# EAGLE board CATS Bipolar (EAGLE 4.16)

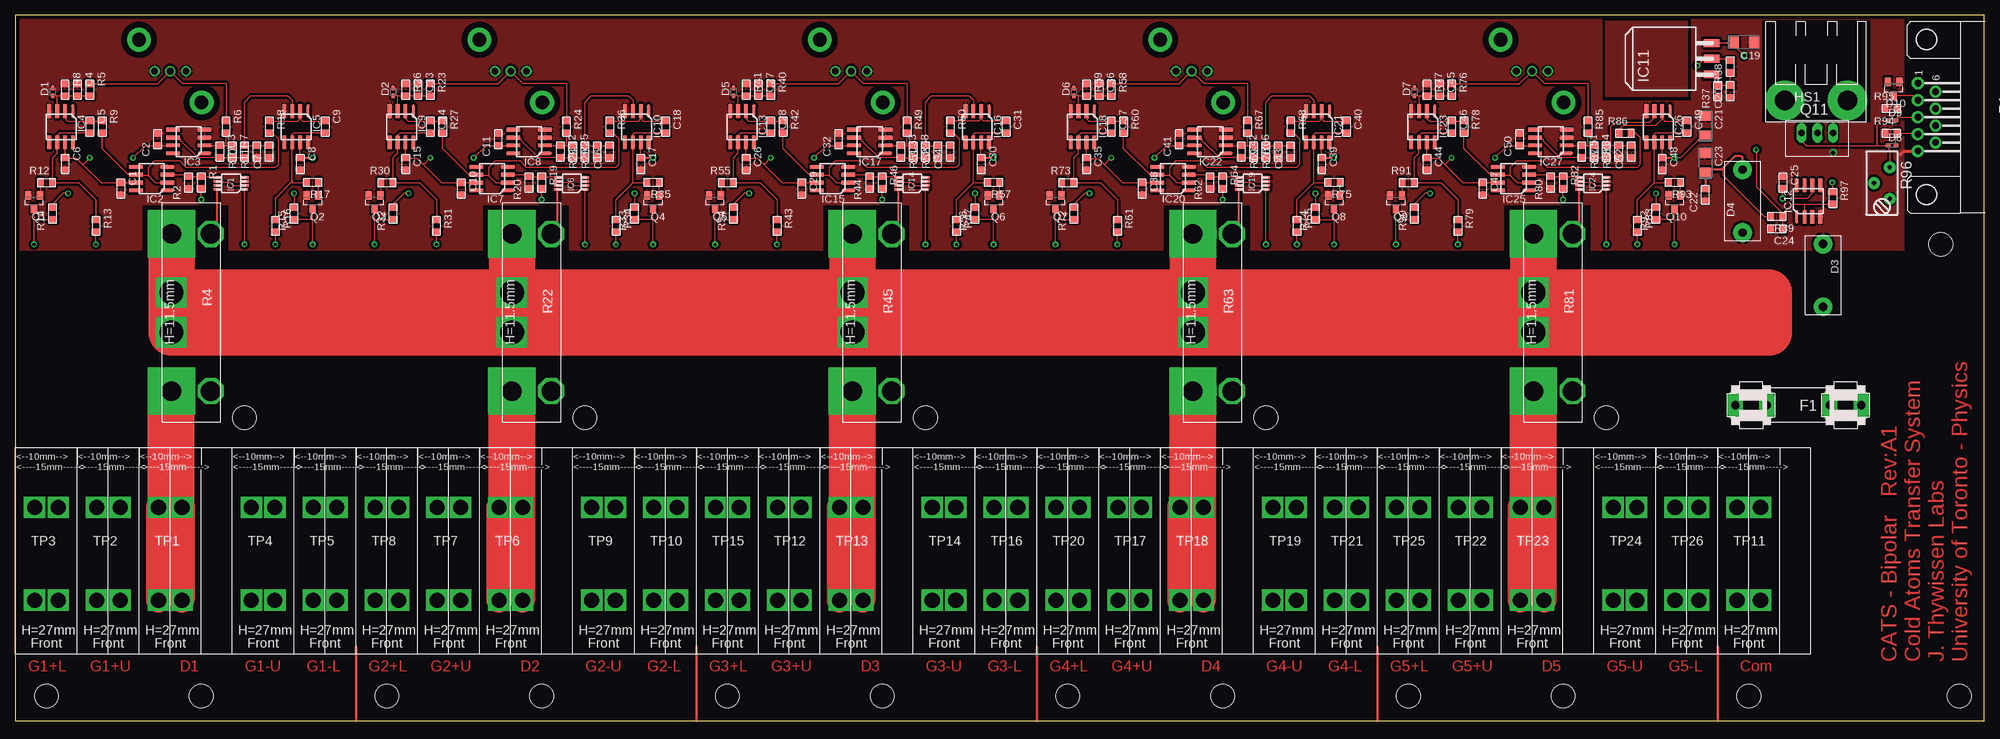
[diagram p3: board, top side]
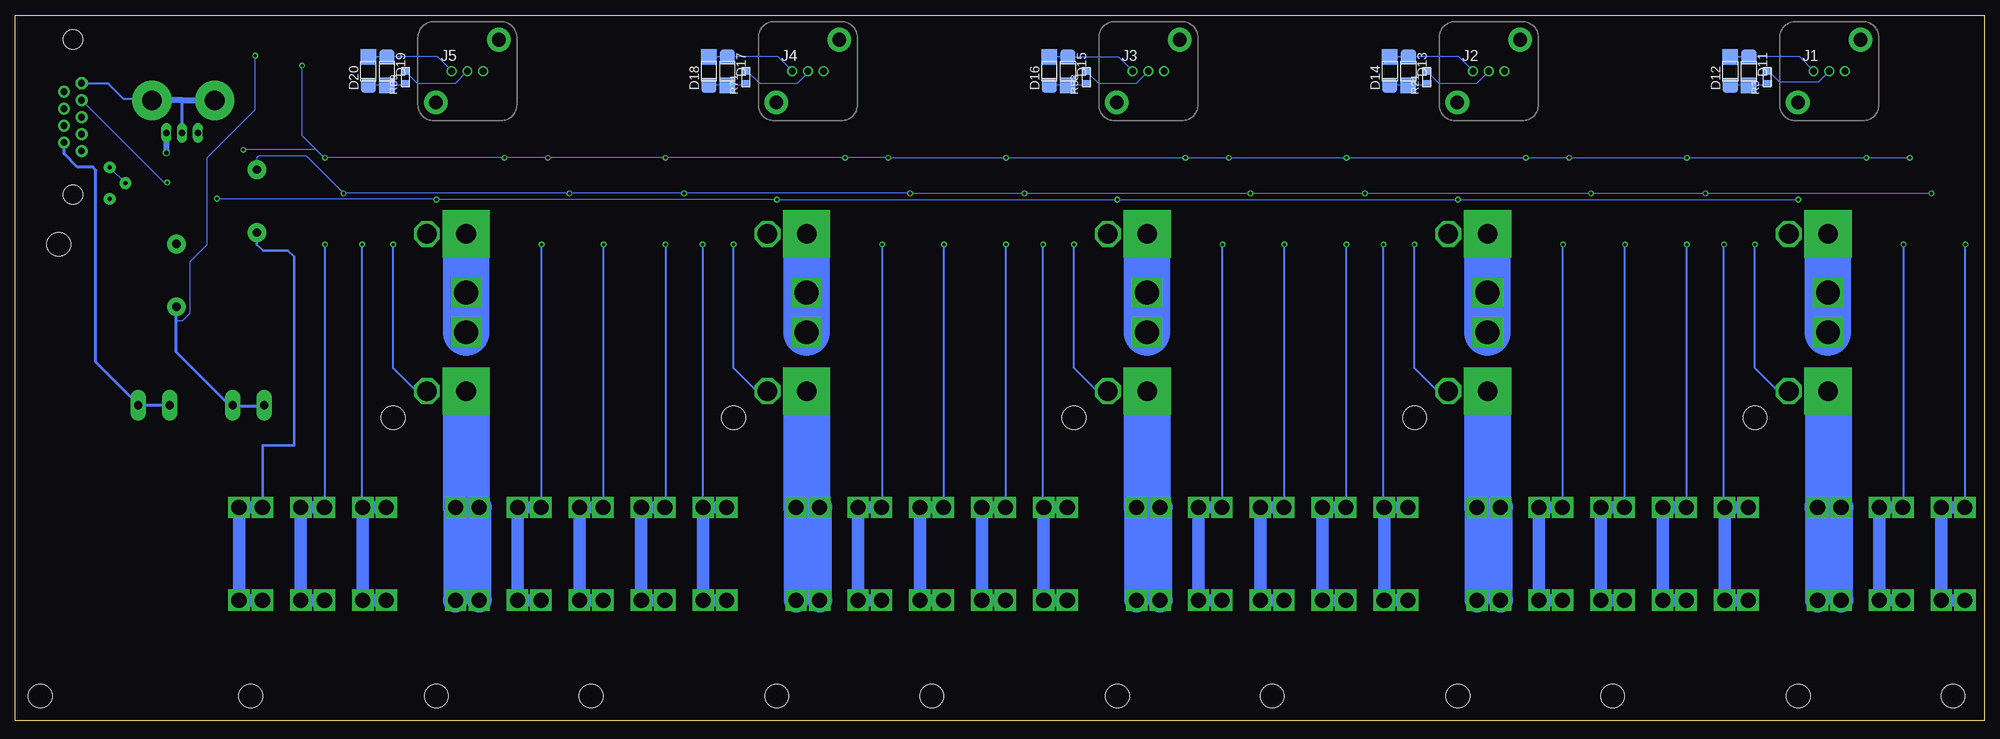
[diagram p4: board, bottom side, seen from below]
Size 318 x 114 mm. Coordinates in mm from the lower left corner, seen from the top.
Outline: 0,0 318,0 318,114 0,114 0,0
Copper layers (1*16): Top 0.035mm / dielectric 1.5mm / Bottom 0.035mm
Design rules "DRC standard check (7mil trace and gap, 20mil drill, etc)": minimum track width 7mil, minimum drill 20mil, track to track 7mil, track to pad 7mil, pad to pad 7mil, via to via 7mil, smd to smd 7mil, copper to edge 25mil, drill to drill 8mil, minimum pad ring 10mil, minimum via ring 8mil, stop-mask expansion 4mil, vias tented up to drill 0mil, thermal gap 10mil
Net classes: 0 default: clearance 0.406 mm; 1 Power: width 1.016 mm, drill 0.178 mm, clearance 3.175 mm
Holes 3.86 mm at 5,4 30,4 60,4 85,4 115,4 140,4 170,4 195,4 225,4 250,4 280,4 314,4 311,77 37,49 92,49 147,49 202,49 257,49
bKeepout: area 1.5,0.5 to 8.5,7.5; area 26.5,0.5 to 33.5,7.5; area 56.5,0.5 to 63.5,7.5; area 81.5,0.5 to 88.5,7.5; area 111.5,0.5 to 118.5,7.5; area 136.5,0.5 to 143.5,7.5; area 166.5,0.5 to 173.5,7.5; area 191.5,0.5 to 198.5,7.5; area 221.5,0.5 to 228.5,7.5; area 246.5,0.5 to 253.5,7.5; area 276.5,0.5 to 283.5,7.5; area 310.5,0.5 to 317.5,7.5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
tRestrict: 23 lines

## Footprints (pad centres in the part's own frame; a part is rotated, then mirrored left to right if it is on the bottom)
2012(0805) = smd 1.016 x 1.397: 1 -0.953,0; 2 0.953,0
EIA-A = smd 1.6 x 1.8: 1 -1.27,0; 2 1.905,0
SOD523 = smd 0.7 x 0.5: A 1.27,0; C 0,0
PASSIVE_0.4" = drill 1.321 pad 3.048 round: 1 -5.08,0; 2 5.08,0
SOT23 = smd 1 x 1.4: 1 -0.953,-0.953; 2 0.953,-0.953; 3 0,1.27
1209 = smd 2.5 x 2.5: A 2.3,0; K -2.3,0
FUSE = drill 1.321 pad 2.54 long: 1A -10.16,0; 1B -5.08,0; 2A 10.16,0; 2B 5.08,0
HEATSINK-5(TO-220) = drill 3.175 pad 6.35 round: 1 -5.08,0; 2 5.08,0
MSOP8 = smd 0.4 x 1.2: 1 -0.635,-1.905; 2 0,-1.905; 3 0.635,-1.905; 4 1.27,-1.905; 5 1.27,2.54; 6 0.635,2.54; 7 0,2.54; 8 -0.635,2.54
SOIC-8 = smd 0.6 x 2.2: 1 -1.27,-2.54; 2 0,-2.54; 3 1.27,-2.54; 4 2.54,-2.54; 5 2.54,2.54; 6 1.27,2.54; 7 0,2.54; 8 -1.27,2.54
TO263 = smd 1.27 x 2.54: 1 -2.54,0; 2 0,0; 3 2.54,0
CONN-BNC-AMP-TYPE1VERT = drill 1.067 round: CONDUCTOR 0,0; SHIELD1 -2.54,0; SHIELD2 2.54,0 | drill 2.184 pad 3.81 round: MTG1 -5.08,-5.08; MTG2 5.08,5.08
CONN-DB9-HORIZ1 = drill 1.067 pad 1.905 octagon: 1 -5.486,-1.422 | drill 1.067 pad 1.905 round: 2 -2.743,-1.422; 3 0,-1.422; 4 2.743,-1.422; 5 5.486,-1.422; 6 -4.115,1.422; 7 -1.372,1.422; 8 1.372,1.422; 9 4.115,1.422 | hole 3.175: -12.522,0; 12.522,0
TO220-VERTICAL = drill 1.067 long: 1 -2.54,0; 2 0,0; 3 2.54,0
OHMITE_650 = drill 3.175 pad 7.62 square: CURRENT1 -12.7,-3.81; CURRENT2 12.7,-3.81 | drill 3.175 octagon: SENSE1 -12.7,2.54; SENSE2 12.7,2.54
BOURNS-3296Y = drill 0.711 pad 1.905 round: CCW 2.54,1.27; CW -2.54,1.27; W 0,-1.27
PHEONIX_ZFKDS-10/15MM-TERMINAL-BLOCK = drill 2.438 square: T@1 -1.9,-7.5; T@2 1.9,-7.5; T@3 1.9,7.5; T@4 -1.9,7.5

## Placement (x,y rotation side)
C1  0.1uF  [2012(0805)]  17,86 270 top
C2  0.1uF  [2012(0805)]  23,94 90 top
C3  1nF  [2012(0805)]  33,92 270 top
C4  10nF  [2012(0805)]  10,102 270 top
C5  100pF  [2012(0805)]  12,96 270 top
C6  0.1uF  [2012(0805)]  8,90 270 top
C7  10nF  [2012(0805)]  41,92 90 top
C8  0.1uF  [2012(0805)]  46,90 270 top
C9  100pF  [2012(0805)]  50,96 270 top
C10  0.1uF  [2012(0805)]  72,86 270 top
C11  0.1uF  [2012(0805)]  78,94 90 top
C12  1nF  [2012(0805)]  88,92 270 top
C13  10nF  [2012(0805)]  65,102 270 top
C14  100pF  [2012(0805)]  67,96 270 top
C15  0.1uF  [2012(0805)]  63,90 270 top
C16  10nF  [2012(0805)]  96,92 90 top
C17  0.1uF  [2012(0805)]  101,90 270 top
C18  100pF  [2012(0805)]  105,96 270 top
C19  100uF/35V  [EIA-A]  279.5,109.65 180 top
C20  0.1uF  [2012(0805)]  277,101.75 90 top
C21  100uF/35V  [EIA-A]  273,96.5 270 top
C22  0.1uF  [2012(0805)]  273,85 90 top
C23  100uF/35V  [EIA-A]  273,90.5 270 top
C24  0.1uF  [2012(0805)]  284.5,79.5 180 top
C25  0.1uF  [2012(0805)]  285.5,87 270 top
C26  0.1uF  [2012(0805)]  118,90 270 top
C27  10nF  [2012(0805)]  120,102 270 top
C28  100pF  [2012(0805)]  122,96 270 top
C29  0.1uF  [2012(0805)]  127,86 270 top
C30  0.1uF  [2012(0805)]  156,90 270 top
C31  100pF  [2012(0805)]  160,96 270 top
C32  0.1uF  [2012(0805)]  133,94 90 top
C33  1nF  [2012(0805)]  143,92 270 top
C34  10nF  [2012(0805)]  151,92 90 top
C35  0.1uF  [2012(0805)]  173,90 270 top
C36  10nF  [2012(0805)]  175,102 270 top
C37  100pF  [2012(0805)]  177,96 270 top
C38  0.1uF  [2012(0805)]  182,86 270 top
C39  0.1uF  [2012(0805)]  211,90 270 top
C40  100pF  [2012(0805)]  215,96 270 top
C41  0.1uF  [2012(0805)]  188,94 90 top
C42  1nF  [2012(0805)]  198,92 270 top
C43  10nF  [2012(0805)]  206,92 90 top
C44  0.1uF  [2012(0805)]  228,90 270 top
C45  10nF  [2012(0805)]  230,102 270 top
C46  100pF  [2012(0805)]  232,96 270 top
C47  0.1uF  [2012(0805)]  237,86 270 top
C48  0.1uF  [2012(0805)]  266,90 270 top
C49  100pF  [2012(0805)]  270,96 270 top
C50  0.1uF  [2012(0805)]  243,94 90 top
C51  1nF  [2012(0805)]  253,92 270 top
C52  10nF  [2012(0805)]  261,92 90 top
D1  1N4148WT  [SOD523]  6,101 90 top
D2  1N4148WT  [SOD523]  61,101 90 top
D3  1N4750A  [PASSIVE_0.4"]  292,72 270 top
D4  1N4740A  [PASSIVE_0.4"]  279,84 90 top
D5  1N4148WT  [SOD523]  116,101 90 top
D6  1N4148WT  [SOD523]  171,101 90 top
D7  1N4148WT  [SOD523]  226,101 90 top
D8  1N4148WT  [SOD523]  302.5,93 0 top
D9  1N4148WT  [SOD523]  302.5,97 0 top
D10  BZX84-C5V1  [SOT23]  303.4,102.3 180 top
D11  SML-LXL1209UPGC  [1209]  38,105 270 bottom
D12  SML-LXL1209SOC  [1209]  41,105 90 bottom
D13  SML-LXL1209UPGC  [1209]  93,105 270 bottom
D14  SML-LXL1209SOC  [1209]  96,105 90 bottom
D15  SML-LXL1209UPGC  [1209]  148,105 270 bottom
D16  SML-LXL1209SOC  [1209]  151,105 90 bottom
D17  SML-LXL1209UPGC  [1209]  203,105 270 bottom
D18  SML-LXL1209SOC  [1209]  206,105 90 bottom
D19  SML-LXL1209UPGC  [1209]  258,105 270 bottom
D20  SML-LXL1209SOC  [1209]  261,105 90 bottom
F1  0.1A-5x20  [FUSE]  288,51 180 top
HS1  634-20ABP  [HEATSINK-5(TO-220)]  290.89,100.28 0 top
IC1  AD8212RMZ  [MSOP8]  35.15,86.54 90 top
IC2  AD820ARZ  [SOIC-8]  22,87 90 top
IC3  AD820ARZ  [SOIC-8]  28,93 90 top
IC4  AD820ARZ  [SOIC-8]  8,96 180 top
IC5  AD820ARZ  [SOIC-8]  46,96 180 top
IC6  AD8212RMZ  [MSOP8]  90.15,86.54 90 top
IC7  AD820ARZ  [SOIC-8]  77,87 90 top
IC8  AD820ARZ  [SOIC-8]  83,93 90 top
IC9  AD820ARZ  [SOIC-8]  63,96 180 top
IC10  AD820ARZ  [SOIC-8]  101,96 180 top
IC11  LM1086CS-ADJ  [TO263]  274,107 90 top
IC12  ADR435AR(Z)  [SOIC-8]  289,84 0 top
IC13  AD820ARZ  [SOIC-8]  118,96 180 top
IC14  AD8212RMZ  [MSOP8]  145.15,86.54 90 top
IC15  AD820ARZ  [SOIC-8]  132,87 90 top
IC16  AD820ARZ  [SOIC-8]  156,96 180 top
IC17  AD820ARZ  [SOIC-8]  138,93 90 top
IC18  AD820ARZ  [SOIC-8]  173,96 180 top
IC19  AD8212RMZ  [MSOP8]  200.15,86.54 90 top
IC20  AD820ARZ  [SOIC-8]  187,87 90 top
IC21  AD820ARZ  [SOIC-8]  211,96 180 top
IC22  AD820ARZ  [SOIC-8]  193,93 90 top
IC23  AD820ARZ  [SOIC-8]  228,96 180 top
IC24  AD8212RMZ  [MSOP8]  255.15,86.54 90 top
IC25  AD820ARZ  [SOIC-8]  242,87 90 top
IC26  AD820ARZ  [SOIC-8]  266,96 180 top
IC27  AD820ARZ  [SOIC-8]  248,93 90 top
J1  Amp 227673-1  [CONN-BNC-AMP-TYPE1VERT]  25,105 0 bottom
J2  Amp 227673-1  [CONN-BNC-AMP-TYPE1VERT]  80,105 0 bottom
J3  Amp 227673-1  [CONN-BNC-AMP-TYPE1VERT]  135,105 0 bottom
J4  Amp 227673-1  [CONN-BNC-AMP-TYPE1VERT]  190,105 0 bottom
J5  Amp 227673-1  [CONN-BNC-AMP-TYPE1VERT]  245,105 0 bottom
P1  [CONN-DB9-HORIZ1]  308.74,97.57 270 top
Q1  MMBT5551  [SOT23]  3,84 180 top
Q2  MMBT5551  [SOT23]  48,84 180 top
Q3  MMBT5551  [SOT23]  58,84 180 top
Q4  MMBT5551  [SOT23]  103,84 180 top
Q5  MMBT5551  [SOT23]  113,84 180 top
Q6  MMBT5551  [SOT23]  158,84 180 top
Q7  MMBT5551  [SOT23]  168,84 180 top
Q8  MMBT5551  [SOT23]  213,84 180 top
Q9  MMBT5551  [SOT23]  223,84 180 top
Q10  MMBT5551  [SOT23]  268,84 180 top
Q11  NDP6060L  [TO220-VERTICAL]  291.08,95.04 0 top
R1  75K  [2012(0805)]  30,87 270 top
R2  3.92K  [2012(0805)]  28,87 90 top
R3  3.01K  [2012(0805)]  35,104 90 bottom
R4  2mOhm/5W  [OHMITE_650]  29,66 270 top
R5  9.09K  [2012(0805)]  12,102 270 top
R6  10K  [2012(0805)]  34,96 270 top
R7  10K  [2012(0805)]  35,92 270 top
R8  1K  [2012(0805)]  8,102 270 top
R9  3.92K  [2012(0805)]  14,96 270 top
R10  9.09K  [2012(0805)]  37,92 90 top
R11  1K  [2012(0805)]  39,92 90 top
R12  10K  [2012(0805)]  5,87 0 top
R13  100  [2012(0805)]  13,80 270 top
R14  2K  [2012(0805)]  6,82 90 top
R15  2K  [2012(0805)]  45,82 90 top
R16  100  [2012(0805)]  42,80 270 top
R17  10K  [2012(0805)]  48,87 180 top
R18  3.92K  [2012(0805)]  41,96 270 top
R19  75K  [2012(0805)]  85,87 270 top
R20  3.92K  [2012(0805)]  83,87 90 top
R21  3.01K  [2012(0805)]  90,104 90 bottom
R22  2mOhm/5W  [OHMITE_650]  84,66 270 top
R23  9.09K  [2012(0805)]  67,102 270 top
R24  10K  [2012(0805)]  89,96 270 top
R25  10K  [2012(0805)]  90,92 270 top
R26  1K  [2012(0805)]  63,102 270 top
R27  3.92K  [2012(0805)]  69,96 270 top
R28  9.09K  [2012(0805)]  92,92 90 top
R29  1K  [2012(0805)]  94,92 90 top
R30  10K  [2012(0805)]  60,87 0 top
R31  100  [2012(0805)]  68,80 270 top
R32  2K  [2012(0805)]  61,82 90 top
R33  2K  [2012(0805)]  100,82 90 top
R34  100  [2012(0805)]  97,80 270 top
R35  10K  [2012(0805)]  103,87 180 top
R36  3.92K  [2012(0805)]  96,96 270 top
R37  1.47K  [2012(0805)]  275,101.75 90 top
R38  124  [2012(0805)]  277,105.75 90 top
R39  301  [2012(0805)]  284.5,81.5 180 top
R40  9.09K  [2012(0805)]  122,102 270 top
R41  1K  [2012(0805)]  118,102 270 top
R42  3.92K  [2012(0805)]  124,96 270 top
R43  100  [2012(0805)]  123,80 270 top
R44  3.92K  [2012(0805)]  138,87 90 top
R45  2mOhm/5W  [OHMITE_650]  139,66 270 top
R46  75K  [2012(0805)]  140,87 270 top
R47  100  [2012(0805)]  152,80 270 top
R48  10K  [2012(0805)]  145,92 270 top
R49  10K  [2012(0805)]  144,96 270 top
R50  3.92K  [2012(0805)]  151,96 270 top
R51  9.09K  [2012(0805)]  147,92 90 top
R52  1K  [2012(0805)]  149,92 90 top
R53  3.01K  [2012(0805)]  145,104 90 bottom
R54  2K  [2012(0805)]  116,82 90 top
R55  10K  [2012(0805)]  115,87 0 top
R56  2K  [2012(0805)]  155,82 90 top
R57  10K  [2012(0805)]  158,87 180 top
R58  9.09K  [2012(0805)]  177,102 270 top
R59  1K  [2012(0805)]  173,102 270 top
R60  3.92K  [2012(0805)]  179,96 270 top
R61  100  [2012(0805)]  178,80 270 top
R62  3.92K  [2012(0805)]  193,87 90 top
R63  2mOhm/5W  [OHMITE_650]  194,66 270 top
R64  75K  [2012(0805)]  195,87 270 top
R65  100  [2012(0805)]  207,80 270 top
R66  10K  [2012(0805)]  200,92 270 top
R67  10K  [2012(0805)]  199,96 270 top
R68  3.92K  [2012(0805)]  206,96 270 top
R69  9.09K  [2012(0805)]  202,92 90 top
R70  1K  [2012(0805)]  204,92 90 top
R71  3.01K  [2012(0805)]  200,104 90 bottom
R72  2K  [2012(0805)]  171,82 90 top
R73  10K  [2012(0805)]  170,87 0 top
R74  2K  [2012(0805)]  210,82 90 top
R75  10K  [2012(0805)]  213,87 180 top
R76  9.09K  [2012(0805)]  232,102 270 top
R77  1K  [2012(0805)]  228,102 270 top
R78  3.92K  [2012(0805)]  234,96 270 top
R79  100  [2012(0805)]  233,80 270 top
R80  3.92K  [2012(0805)]  248,87 90 top
R81  2mOhm/5W  [OHMITE_650]  249,66 270 top
R82  75K  [2012(0805)]  250,87 270 top
R83  100  [2012(0805)]  262,80 270 top
R84  10K  [2012(0805)]  255,92 270 top
R85  10K  [2012(0805)]  254,96 270 top
R86  3.92K  [2012(0805)]  260,95 0 top
R87  9.09K  [2012(0805)]  257,92 90 top
R88  1K  [2012(0805)]  259,92 90 top
R89  3.01K  [2012(0805)]  255,104 90 bottom
R90  2K  [2012(0805)]  226,82 90 top
R91  10K  [2012(0805)]  225,87 0 top
R92  2K  [2012(0805)]  265,82 90 top
R93  10K  [2012(0805)]  268,87 180 top
R94  ???  [2012(0805)]  303,95 0 top
R95  ???  [2012(0805)]  303,99 0 top
R96  3296Y-10K  [BOURNS-3296Y]  301.5,86.9 270 top
R97  1K  [2012(0805)]  293.55,84.5 270 top
TP1  Pheonix-1987631  [PHEONIX_ZFKDS-10/15MM-TERMINAL-BLOCK]  25,27 0 top
TP2  Pheonix-1987628  [PHEONIX_ZFKDS-10/15MM-TERMINAL-BLOCK]  15,27 0 top
TP3  Pheonix-1987628  [PHEONIX_ZFKDS-10/15MM-TERMINAL-BLOCK]  5,27 0 top
TP4  Pheonix-1987628  [PHEONIX_ZFKDS-10/15MM-TERMINAL-BLOCK]  40,27 0 top
TP5  Pheonix-1987628  [PHEONIX_ZFKDS-10/15MM-TERMINAL-BLOCK]  50,27 0 top
TP6  Pheonix-1987631  [PHEONIX_ZFKDS-10/15MM-TERMINAL-BLOCK]  80,27 0 top
TP7  Pheonix-1987628  [PHEONIX_ZFKDS-10/15MM-TERMINAL-BLOCK]  70,27 0 top
TP8  Pheonix-1987628  [PHEONIX_ZFKDS-10/15MM-TERMINAL-BLOCK]  60,27 0 top
TP9  Pheonix-1987628  [PHEONIX_ZFKDS-10/15MM-TERMINAL-BLOCK]  95,27 0 top
TP10  Pheonix-1987628  [PHEONIX_ZFKDS-10/15MM-TERMINAL-BLOCK]  105,27 0 top
TP11  Pheonix-1987628  [PHEONIX_ZFKDS-10/15MM-TERMINAL-BLOCK]  280,27 0 top
TP12  Pheonix-1987628  [PHEONIX_ZFKDS-10/15MM-TERMINAL-BLOCK]  125,27 0 top
TP13  Pheonix-1987631  [PHEONIX_ZFKDS-10/15MM-TERMINAL-BLOCK]  135,27 0 top
TP14  Pheonix-1987628  [PHEONIX_ZFKDS-10/15MM-TERMINAL-BLOCK]  150,27 0 top
TP15  Pheonix-1987628  [PHEONIX_ZFKDS-10/15MM-TERMINAL-BLOCK]  115,27 0 top
TP16  Pheonix-1987628  [PHEONIX_ZFKDS-10/15MM-TERMINAL-BLOCK]  160,27 0 top
TP17  Pheonix-1987628  [PHEONIX_ZFKDS-10/15MM-TERMINAL-BLOCK]  180,27 0 top
TP18  Pheonix-1987631  [PHEONIX_ZFKDS-10/15MM-TERMINAL-BLOCK]  190,27 0 top
TP19  Pheonix-1987628  [PHEONIX_ZFKDS-10/15MM-TERMINAL-BLOCK]  205,27 0 top
TP20  Pheonix-1987628  [PHEONIX_ZFKDS-10/15MM-TERMINAL-BLOCK]  170,27 0 top
TP21  Pheonix-1987628  [PHEONIX_ZFKDS-10/15MM-TERMINAL-BLOCK]  215,27 0 top
TP22  Pheonix-1987628  [PHEONIX_ZFKDS-10/15MM-TERMINAL-BLOCK]  235,27 0 top
TP23  Pheonix-1987631  [PHEONIX_ZFKDS-10/15MM-TERMINAL-BLOCK]  245,27 0 top
TP24  Pheonix-1987628  [PHEONIX_ZFKDS-10/15MM-TERMINAL-BLOCK]  260,27 0 top
TP25  Pheonix-1987628  [PHEONIX_ZFKDS-10/15MM-TERMINAL-BLOCK]  225,27 0 top
TP26  Pheonix-1987628  [PHEONIX_ZFKDS-10/15MM-TERMINAL-BLOCK]  270,27 0 top
U$106  [TITLEBLOCK_PCB]  not placed on the board

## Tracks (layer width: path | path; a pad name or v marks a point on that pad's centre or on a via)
+5.0V  (via drill 0.51)
  Top 0.18: v30,84.25 R1.2 | v85,84.25 R19.2 | v140,84.25 R46.2 | R64.2 v195,84.25 | v250,84.25 R82.2 | IC12.6 290.27,85.27 289.5,84.5 285.5,84.5 | 285.5,84.5 285.45,84.5 v285.45,84.4 | 285.5,84.5 C25.2
  Bottom 0.18: v30,84.25 v85,84.25 v140,84.25 v195,84.25 v250,84.25 | v250,84.25 250,84.2 | v250,84.25 250,84.3 285.35,84.3 285.35,84.35 285.5,84.5 285.45,84.5 v285.45,84.4
+10V  (via drill 0.51)
  Top 0.18: R14.2 6,83.5 7.75,85.25 v8.5,85.25 | R32.2 61,83.5 62.75,85.25 v63.5,85.25 | v45,85.25 R15.2 | v100,85.25 R33.2 | R54.2 116,83.5 117.75,85.25 v118.5,85.25 | v155,85.25 R56.2 | R72.2 171,83.5 172.75,85.25 v173.5,85.25 | v210,85.25 R74.2 | R90.2 226,83.5 227.75,85.25 v228.5,85.25 | v265,85.25 R92.2 | C23.2 273,88.5 273.58,89.08 | R39.2 282.5,81.5 275.8,88.2 275.8,89.08
  Top 0.36: 273.58,89.08 275.8,89.08 275.75,89.25 277.75,91.25 278.75,91.25 279,91 D4.2 | C23.2 C22.2
  Bottom 0.18: v8.5,85.25 v45,85.25 v63.5,85.25 v100,85.25 v118.5,85.25 v155,85.25 v173.5,85.25 v210,85.25 v228.5,85.25 v265,85.25 271,91.25 278.75,91.25 279,91 279,89 D4.2
+16V  (via drill 0.51)
  Top 0.18: IC4.7 8,91 8.1,90.9 C6.1 7.9,90.9 9.9,90.9 10.9,89.9 | IC2.7 17.1,87 17,86.9 C1.1 13.85,86.95 10.9,89.9 | 23,93 22.9,93 22.9,93.05 C2.1 23,93 | 23,93 IC3.7 | 46,93.5 IC5.7 C8.1 | 10.9,89.9 10.9,90 11,90 v12,91 | v19,91 21,93 23,93 | IC9.7 63,91 63.1,90.9 C15.1 62.9,90.9 64.9,90.9 65.9,89.9 | IC7.7 72.1,87 72,86.9 C10.1 68.85,86.95 65.9,89.9 | 78,93 77.9,93 77.9,93.05 C11.1 78,93 | 78,93 IC8.7 | 101,93.5 IC10.7 C17.1 | 65.9,89.9 65.9,90 66,90 v67,91 | v74,91 76,93 78,93 | IC13.7 118,91 118.1,90.9 C26.1 117.9,90.9 119.9,90.9 120.9,89.9 | IC15.7 127.1,87 127,86.9 C29.1 123.85,86.95 120.9,89.9 | 133,93 132.9,93 132.9,93.05 C32.1 133,93 | 133,93 IC17.7 | 156,93.5 IC16.7 C30.1 | 120.9,89.9 120.9,90 121,90 v122,91 | v129,91 131,93 133,93 | IC18.7 173,91 173.1,90.9 C35.1 172.9,90.9 174.9,90.9 175.9,89.9 | IC20.7 182.1,87 182,86.9 C38.1 178.85,86.95 175.9,89.9 | 188,93 187.9,93 187.9,93.05 C41.1 188,93 | 188,93 IC22.7 | 211,93.5 IC21.7 C39.1 | 175.9,89.9 175.9,90 176,90 v177,91 | v184,91 186,93 188,93 | IC23.7 228,91 228.1,90.9 C44.1 227.9,90.9 229.9,90.9 230.9,89.9 | IC25.7 237.1,87 237,86.9 C47.1 233.85,86.95 230.9,89.9 | 243,93 242.9,93 242.9,93.05 C50.1 243,93 | 243,93 IC27.7 | 266,93.5 IC26.7 C48.1 | 230.9,89.9 230.9,90 231,90 v232,91 | v239,91 241,93 243,93 | v268,91 269,91 272,94 272.4,94 C21.2 | 285.5,81.5 R39.1 | C24.1 285.45,81.45 285.5,81.5 | 285.5,82 285.5,81.5 | 285.5,82 287,83.5 289,83.5 | 289,83.5 IC12.2 | R38.2 277,106.75 276.75,107 IC11.2 272.8,107 v271.7,105.9 | R97.2 293.5,83.55 293.5,83.5 289,83.5 | C21.2 | C21.2 273,94.75 | 285.5,82 281.2,86.3 v281.2,92.3
  Top 0.36: C8.1 47.95,90.95 v48,91 | C17.1 102.95,90.95 v103,91 | C30.1 157.95,90.95 v158,91 | C39.1 212.95,90.95 v213,91 | C48.1 267.95,90.95 v268,91
  Bottom 0.18: v12,91 v19,91 v48,91 v67,91 v74,91 v103,91 v122,91 v129,91 v158,91 v177,91 v184,91 v213,91 v232,91 v239,91 v268,91 268.1,91 269.4,92.3 | v271.7,105.9 271.7,94.6 269.4,92.3 | 269.4,92.3 v281.2,92.3
  pour Top: 257,101 270,101 270,113 257,113
+V-COIL  (via drill 3.86)
  Top 2: R4.CURRENT1 | R22.CURRENT1 | R45.CURRENT1 | R63.CURRENT1 | R81.CURRENT1
  Top 7.5: v25.2,69.2 R4.CURRENT1 | v25.2,69.2 v25.2,62.8 v80.2,62.8 | v80.2,69.2 R22.CURRENT1 | v80.2,69.2 v80.2,62.8 | v80.2,69.2 v25.2,69.2 | v135.2,69.2 R45.CURRENT1 | v135.2,69.2 v135.2,62.8 | v135.2,69.2 v80.2,69.2 | v135.2,62.8 v80.2,62.8 | v190.2,69.2 R63.CURRENT1 | v190.2,69.2 v190.2,62.8 | v190.2,69.2 v135.2,69.2 | v190.2,62.8 v135.2,62.8 | v245.2,69.2 R81.CURRENT1 | v245.2,69.2 v245.2,62.8 | v190.2,69.2 v245.2,69.2 | v190.2,62.8 v245.2,62.8 | v245.2,62.8 283.2,62.8 283.2,69.2 v245.2,69.2
  Bottom 7.5: R4.CURRENT1 v25.2,69.2 v25.2,62.8 | R22.CURRENT1 v80.2,69.2 v80.2,62.8 | R45.CURRENT1 v135.2,69.2 v135.2,62.8 | R63.CURRENT1 v190.2,69.2 v190.2,62.8 | R81.CURRENT1 v245.2,69.2 v245.2,62.8
AGND  (via drill 0.71)
  Top 0.5: P1.5 305.08,92.08 304.5,91.5
  Bottom 0.18: v293.62,91.82 293.6,91.8 | D11.K 40.7,107.3 40.75,107.25 40.75,107.3 D12.A 29.8,107.3 27.5,105 J1.SHIELD1 | D13.K 93,107.25 93.05,107.3 D14.A 84.8,107.3 82.5,105 J2.SHIELD1 | D15.K 150.95,107.3 151,107.25 D16.A 139.8,107.3 137.5,105 J3.SHIELD1 | D17.K 205.95,107.3 206,107.25 D18.A 194.8,107.3 192.5,105 J4.SHIELD1 | D19.K 260.95,107.3 261,107.25 D20.A 249.8,107.3 247.5,105 J5.SHIELD1
  Bottom 0.4: D4.1 279,77 278,76 274,76 273,75 273,74
  Bottom 0.406: TP11.T@4 278.1,44.5 273,44.5 273,74
  Bottom 1: 293.6,91.8 293.6,95
  Bottom 2: TP11.T@1 TP11.T@2 TP11.T@3 TP11.T@4
  pour Top (rank 2): 305,114 305,76 0,76 0,114
N$1
  Top 0.18: IC2.3 27.63,88.27 28,87.9 R2.2 29.95,87.95 30,87.9 R1.1 32.45,87.95 IC1.5
N$2
  Top 0.18: R9.2 14,92.5 18.23,88.27 IC2.6 19.4,88.27 19.3,88.2 21.4,88.2 21.55,88.05 | IC2.2 22.6,87 21.55,88.05 | R18.2 41.45,95.05 42.5,94 42.5,90 42,89.5 27.5,89.5 26.5,90.5 22.5,90.5 21.5,89.5 21.5,88 21.55,88 21.55,88.05
N$3  (via drill 0.51)
  Top 0.18: IC1.1 37.05,86 37,86 v37,77
  Bottom 0.36: R4.SENSE2 33.3,53.3 37,57 v37,77
N$4
  Top 0.36: R4.SENSE1 31.54,78.5 31.5,78.5 32.61,79.61 IC1.8
N$5
  Top 0.18: IC1.2 35.16,86.54 34.6,87.1 32.8,87.1 32.7,87.17 IC1.6
N$6
  Top 0.18: 34,96.9 R6.1 34,103.05 26.95,103.05 J1.CONDUCTOR 22.95,102.95 R5.1
  Bottom 0.18: R3.2 34.7,104.95 33,103.25 26.75,103.25 J1.CONDUCTOR
N$7
  Top 0.18: 46,97.3 IC5.2 | 46,97.3 46.4,96.9 49.9,96.9 50,97 C9.1 | R18.1 45.65,96.95 46,97.3
N$8
  Top 4: TP1.T@1 TP1.T@4 25.2,34.5 | TP1.T@2 TP1.T@3 25.2,34.5 | 25.2,34.5 25.19,34.5
  Top 7.6: 25.19,34.5 R4.CURRENT2
  Bottom 4: TP1.T@1 TP1.T@4 | TP1.T@3 TP1.T@2
  Bottom 7.6: R4.CURRENT2 25.19,34.5
N$9
  Top 0.18: C9.2 50,95 49.9,95.1 45,95.1 44.73,94.83 IC5.6 44.73,87.23 | 44.73,87.23 44.73,87 R17.2 | 44.73,87.23 42,84.5 R16.1
N$10  (via drill 0.51)
  Top 0.18: v42,77 R16.2
  Bottom 0.18: TP4.T@3 42,34.5
  Bottom 0.36: 42,34.5 v42,77
  Bottom 2: TP4.T@1 TP4.T@2 TP4.T@3 TP4.T@4
N$11
  Top 0.18: R10.1 35.05,91.05 35,91 R7.2 33.05,91.05 33,91.1 | 33,91.1 C3.2 | 33,91.1 29.4,91.1 26.7,93.8 26.7,94 26.5,94.2 25.5,94.2 25.4,94.3 25.4,94.27 IC3.6
N$12
  Top 0.18: IC3.2 33,93 C3.1 34,92.95 | R7.1 35,92.9 34.95,92.95 34,92.95 | 34,92.95 R6.2
N$13
  Top 0.18: C7.2 39.05,92.95 39,93 R11.2 37.05,92.95 37,93 | IC5.3 44.73,100.27 44,101 38,101 37,100 37,93 | R10.2 37,93
N$14  (via drill 0.51)
  Top 0.18: 6,81 R14.1 3.05,81.05 3,81 | v3,77 3,81 | 3,81 Q1.3
  Bottom 0.18: 3.2,34.5 3.1,34.6 TP3.T@4 3,34.5
  Bottom 0.36: 3,34.5 v3,77
  Bottom 2: TP3.T@1 TP3.T@2 TP3.T@3 3.2,34.5
N$15
  Top 0.18: Q1.1 3.95,85 4,85 4.05,85.05 R12.1
N$16
  Top 0.18: 61.7,101.05 61.05,101.05 D2.C | 61.7,101.05 R26.2 64.95,101.05 65,101 C13.2 66.95,101.05 67,101 R23.2 | 61.7,101.05 61.7,101 61.73,100.97 IC9.3
N$17  (via drill 0.51)
  Top 0.18: v48,77 48,81 | 48,81 Q2.3 | R15.1 47.95,81.05 48,81
  Bottom 0.18: TP5.T@4 48,34.5
  Bottom 0.36: 48,34.5 v48,77
  Bottom 2: TP5.T@1 TP5.T@2 TP5.T@3 TP5.T@4
N$18
  Top 0.18: R17.1 49,87 48.95,86.95 Q2.1
N$19
  Top 0.18: R27.1 67.05,96.95 67,96.9 | IC9.2 63,97.3 63.4,96.9 67,96.9 | 67,96.9 C14.1
N$20
  Top 0.18: C14.2 67,95 66.9,95.1 62.2,95.1 61.73,94.63 IC9.6 61.73,91.73 61,91 61,87 | R30.2 61,87 | 61,87 65.25,87 68,84.25 R31.1 68,80.75
N$21  (via drill 0.51)
  Top 0.18: v68,77 R31.2
  Bottom 0.18: TP7.T@2 71.9,19.6 71.8,19.5 | TP7.T@4 68,34.5
  Bottom 0.36: 68,34.5 v68,77
  Bottom 2: TP7.T@1 71.8,19.5 | TP7.T@2 TP7.T@3 TP7.T@4
N$22
  Bottom 0.18: D14.K 93.05,102.7 93,102.75 D13.A 90.3,102.7 90,103 R21.1
N$23  (via drill 0.51)
  Top 0.18: IC6.1 92.06,86 92,86 v92,77
  Bottom 0.36: R22.SENSE2 88.3,53.3 92,57 v92,77
N$24
  Top 0.36: R22.SENSE1 86.54,78.5 86.5,78.5 87.61,79.61 IC6.8
N$25
  Top 0.18: IC6.2 90.16,86.54 89.6,87.1 87.8,87.1 87.7,87.17 IC6.6
N$26
  Top 4: TP6.T@1 TP6.T@4 80.2,34.5 | TP6.T@2 TP6.T@3 80.2,34.5 | 80.2,34.5 80.19,34.5
  Top 7.6: 80.19,34.5 R22.CURRENT2
  Bottom 4: TP6.T@1 TP6.T@4 | TP6.T@3 TP6.T@2
  Bottom 7.6: R22.CURRENT2 80.19,34.5
N$27
  Top 0.18: IC7.3 82.63,88.27 83,87.9 R20.2 84.95,87.95 85,87.9 R19.1 87.45,87.95 IC6.5
N$28
  Top 0.18: R27.2 69,92.5 73.23,88.27 IC7.6 74.4,88.27 74.3,88.2 76.4,88.2 76.55,88.05 | IC7.2 77.6,87 76.55,88.05 | R36.2 96.45,95.05 97.5,94 97.5,90 97,89.5 82.5,89.5 81.5,90.5 77.5,90.5 76.5,89.5 76.5,88 76.55,88 76.55,88.05
N$29
  Top 0.18: 101,97.3 IC10.2 | 101,97.3 101.4,96.9 104.9,96.9 105,97 C18.1 | R36.1 100.65,96.95 101,97.3
N$30
  Top 0.18: C18.2 105,95 104.9,95.1 100,95.1 99.73,94.83 IC10.6 99.73,87 | 99.73,87 99.73,86.98 97,84.25 R34.1 | 99.73,87 R35.2
N$31  (via drill 0.51)
  Top 0.18: v97,77 R34.2
  Bottom 0.18: TP9.T@3 97,34.5
  Bottom 0.36: 97,34.5 v97,77
  Bottom 2: TP9.T@1 TP9.T@2 TP9.T@3 TP9.T@4
N$32
  Top 0.18: R28.1 90.05,91.05 90,91 R25.2 88.05,91.05 88,91.1 | 88,91.1 C12.2 | 88,91.1 84.4,91.1 81.7,93.8 81.7,94 81.5,94.2 80.5,94.2 80.4,94.3 80.4,94.27 IC8.6
N$33
  Top 0.18: IC8.2 88,93 C12.1 89,92.95 | R25.1 90,92.9 89.95,92.95 89,92.95 | 89,92.95 R24.2
N$34
  Top 0.18: 89,96.9 R24.1 89,103.05 81.95,103.05 J2.CONDUCTOR 77.95,102.95 R23.1
  Bottom 0.18: R21.2 89.95,104.95 88,103 82,103 J2.CONDUCTOR
N$35
  Top 0.18: C16.2 94.05,92.95 94,93 R29.2 92.05,92.95 92,93 | IC10.3 99.73,100.27 99,101 93,101 92,100 92,93 | R28.2 92,93
N$36  (via drill 0.51)
  Top 0.18: 61,81 R32.1 58.05,81.05 58,81 | v58,77 58,81 | 58,81 Q3.3
  Bottom 0.18: 58.2,34.5 58.1,34.6 TP8.T@4 58,34.5
  Bottom 0.36: 58,34.5 v58,77
  Bottom 2: TP8.T@1 TP8.T@2 TP8.T@3 58.2,34.5
N$37
  Top 0.18: Q3.1 58.95,85 59,85 59.05,85.05 R30.1
N$38  (via drill 0.51)
  Top 0.18: v103,77 103,81 | 103,81 Q4.3 | R33.1 102.95,81.05 103,81
  Bottom 0.18: TP10.T@4 103,34.5
  Bottom 0.36: 103,34.5 v103,77
  Bottom 2: TP10.T@1 TP10.T@2 TP10.T@3 TP10.T@4
N$39
  Top 0.18: R35.1 104,87 103.95,86.95 Q4.1
N$40
  Top 0.18: 116.7,101.05 116.05,101.05 D5.C | 116.7,101.05 R41.2 119.95,101.05 120,101 C27.2 121.95,101.05 122,101 R40.2 | 116.7,101.05 116.7,101 116.73,100.97 IC13.3
N$41
  Top 0.18: R42.1 122.05,96.95 122,96.9 | IC13.2 118,97.3 118.4,96.9 122,96.9 | 122,96.9 C28.1
N$42
  Top 0.18: C28.2 122,95 121.9,95.1 117.2,95.1 116.73,94.63 IC13.6 116.73,91.73 116,91 116,87 | R55.2 116,87 | 116,87 120.25,87 123,84.25 R43.1 123,80.75
N$43  (via drill 0.51)
  Top 0.18: v123,77 R43.2
  Bottom 0.18: TP12.T@2 126.9,19.6 126.8,19.5 | TP12.T@4 123,34.5
  Bottom 0.36: 123,34.5 v123,77
  Bottom 2: TP12.T@1 126.8,19.5 | TP12.T@2 TP12.T@3 TP12.T@4
N$44
  Bottom 0.18: D16.K 148.05,102.7 148,102.75 D15.A 145.3,102.7 145,103 R53.1
N$45  (via drill 0.51)
  Top 0.18: IC14.1 147.06,86 147,86 v147,77
  Bottom 0.36: R45.SENSE2 143.3,53.3 147,57 v147,77
N$46
  Top 0.36: R45.SENSE1 141.54,78.5 141.5,78.5 142.61,79.61 IC14.8
N$47
  Top 0.18: IC14.2 145.16,86.54 144.6,87.1 142.8,87.1 142.7,87.17 IC14.6
N$48
  Top 4: TP13.T@1 TP13.T@4 135.2,34.5 | TP13.T@2 TP13.T@3 135.2,34.5 | 135.2,34.5 135.19,34.5
  Top 7.6: 135.19,34.5 R45.CURRENT2
  Bottom 4: TP13.T@1 TP13.T@4 | TP13.T@3 TP13.T@2
  Bottom 7.6: R45.CURRENT2 135.19,34.5
N$49
  Top 0.18: IC15.3 137.63,88.27 138,87.9 R44.2 139.95,87.95 140,87.9 R46.1 142.45,87.95 IC14.5
N$50
  Top 0.18: R42.2 124,92.5 128.23,88.27 IC15.6 129.4,88.27 129.3,88.2 131.4,88.2 131.55,88.05 | IC15.2 132.6,87 131.55,88.05 | R50.2 151.45,95.05 152.5,94 152.5,90 152,89.5 137.5,89.5 136.5,90.5 132.5,90.5 131.5,89.5 131.5,88 131.55,88 131.55,88.05
N$51
  Top 0.18: 156,97.3 IC16.2 | 156,97.3 156.4,96.9 159.9,96.9 160,97 C31.1 | R50.1 155.65,96.95 156,97.3
N$52
  Top 0.18: C31.2 160,95 159.9,95.1 155,95.1 154.73,94.83 IC16.6 154.73,87 | 154.73,87 154.73,86.98 152,84.25 R47.1 | 154.73,87 R57.2
N$53  (via drill 0.51)
  Top 0.18: v152,77 R47.2
  Bottom 0.18: TP14.T@3 152,34.5
  Bottom 0.36: 152,34.5 v152,77
  Bottom 2: TP14.T@1 TP14.T@2 TP14.T@3 TP14.T@4
N$54
  Top 0.18: R51.1 145.05,91.05 145,91 R48.2 143.05,91.05 143,91.1 | 143,91.1 C33.2 | 143,91.1 139.4,91.1 136.7,93.8 136.7,94 136.5,94.2 135.5,94.2 135.4,94.3 135.4,94.27 IC17.6
N$55
  Top 0.18: IC17.2 143,93 C33.1 144,92.95 | R48.1 145,92.9 144.95,92.95 144,92.95 | 144,92.95 R49.2
N$56
  Top 0.18: 144,96.9 R49.1 144,103.05 136.95,103.05 J3.CONDUCTOR 132.95,102.95 R40.1
  Bottom 0.18: R53.2 144.95,104.95 143,103 137,103 J3.CONDUCTOR
N$57
  Top 0.18: C34.2 149.05,92.95 149,93 R52.2 147.05,92.95 147,93 | IC16.3 154.73,100.27 154,101 148,101 147,100 147,93 | R51.2 147,93
N$58  (via drill 0.51)
  Top 0.18: 116,81 R54.1 113.05,81.05 113,81 | v113,77 113,81 | 113,81 Q5.3
  Bottom 0.18: 113.2,34.5 113.1,34.6 TP15.T@4 113,34.5
  Bottom 0.36: 113,34.5 v113,77
  Bottom 2: TP15.T@1 TP15.T@2 TP15.T@3 113.2,34.5
N$59
  Top 0.18: Q5.1 113.95,85 114,85 114.05,85.05 R55.1
N$60  (via drill 0.51)
  Top 0.18: v158,77 158,81 | 158,81 Q6.3 | R56.1 157.95,81.05 158,81
  Bottom 0.18: TP16.T@4 158,34.5
  Bottom 0.36: 158,34.5 v158,77
  Bottom 2: TP16.T@1 TP16.T@2 TP16.T@3 TP16.T@4
N$61
  Top 0.18: R57.1 159,87 158.95,86.95 Q6.1
N$62
  Top 0.18: 171.7,101.05 171.05,101.05 D6.C | 171.7,101.05 R59.2 174.95,101.05 175,101 C36.2 176.95,101.05 177,101 R58.2 | 171.7,101.05 171.7,101 171.73,100.97 IC18.3
N$63
  Top 0.18: R60.1 177.05,96.95 177,96.9 | IC18.2 173,97.3 173.4,96.9 177,96.9 | 177,96.9 C37.1
N$64
  Top 0.18: C37.2 177,95 176.9,95.1 172.2,95.1 171.73,94.63 IC18.6 171.73,91.73 171,91 171,87 | R73.2 171,87 | 171,87 175.25,87 178,84.25 R61.1 178,80.75
N$65  (via drill 0.51)
  Top 0.18: v178,77 R61.2
  Bottom 0.18: TP17.T@2 181.9,19.6 181.8,19.5 | 178,34.5 TP17.T@4
  Bottom 0.36: v178,77 178,34.5
  Bottom 2: 181.8,19.5 TP17.T@1 | TP17.T@2 TP17.T@3 TP17.T@4
N$66
  Bottom 0.18: D18.K 203.05,102.7 203,102.75 D17.A 200.3,102.7 200,103 R71.1
N$67  (via drill 0.51)
  Top 0.18: IC19.1 202.06,86 202,86 v202,77
  Bottom 0.36: R63.SENSE2 198.3,53.3 202,57 v202,77
N$68
  Top 0.36: R63.SENSE1 196.54,78.5 196.5,78.5 197.61,79.61 IC19.8
N$69
  Top 0.18: IC19.2 200.16,86.54 199.6,87.1 197.8,87.1 197.7,87.17 IC19.6
N$70
  Top 4: TP18.T@1 TP18.T@4 190.2,34.5 | TP18.T@2 TP18.T@3 190.2,34.5 | 190.2,34.5 190.19,34.5
  Top 7.6: 190.19,34.5 R63.CURRENT2
  Bottom 4: TP18.T@1 TP18.T@4 | TP18.T@3 TP18.T@2
  Bottom 7.6: R63.CURRENT2 190.19,34.5
N$71
  Top 0.18: IC20.3 192.63,88.27 193,87.9 R62.2 194.95,87.95 195,87.9 R64.1 197.45,87.95 IC19.5
N$72
  Top 0.18: R60.2 179,92.5 183.23,88.27 IC20.6 184.4,88.27 184.3,88.2 186.4,88.2 186.55,88.05 | IC20.2 187.6,87 186.55,88.05 | R68.2 206.45,95.05 207.5,94 207.5,90 207,89.5 192.5,89.5 191.5,90.5 187.5,90.5 186.5,89.5 186.5,88 186.55,88 186.55,88.05
N$73
  Top 0.18: 211,97.3 IC21.2 | 211,97.3 211.4,96.9 214.9,96.9 215,97 C40.1 | R68.1 210.65,96.95 211,97.3
N$74
  Top 0.18: C40.2 215,95 214.9,95.1 210,95.1 209.73,94.83 IC21.6 209.73,87 | 209.73,87 209.73,86.98 207,84.25 R65.1 | 209.73,87 R75.2
N$75  (via drill 0.51)
  Top 0.18: v207,77 R65.2
  Bottom 0.18: 207,34.5 TP19.T@3
  Bottom 0.36: v207,77 207,34.5
  Bottom 2: TP19.T@1 TP19.T@2 TP19.T@3 TP19.T@4
N$76
  Top 0.18: R69.1 200.05,91.05 200,91 R66.2 198.05,91.05 198,91.1 | 198,91.1 C42.2 | 198,91.1 194.4,91.1 191.7,93.8 191.7,94 191.5,94.2 190.5,94.2 190.4,94.3 190.4,94.27 IC22.6
N$77
  Top 0.18: IC22.2 198,93 C42.1 199,92.95 | R66.1 200,92.9 199.95,92.95 199,92.95 | 199,92.95 R67.2
N$78
  Top 0.18: 199,96.9 R67.1 199,103.05 191.95,103.05 J4.CONDUCTOR 187.95,102.95 R58.1
  Bottom 0.18: R71.2 199.7,104.95 197.75,103 191.75,103 190,104.75 J4.CONDUCTOR
N$79
  Top 0.18: C43.2 204.05,92.95 204,93 R70.2 202.05,92.95 202,93 | IC21.3 209.73,100.27 209,101 203,101 202,100 202,93 | R69.2 202,93
N$80  (via drill 0.51)
  Top 0.18: 171,81 R72.1 168.05,81.05 168,81 | v168,77 168,81 | 168,81 Q7.3
  Bottom 0.18: 168.2,34.5 168.1,34.6 TP20.T@4 168,34.5
  Bottom 0.36: 168,34.5 v168,77
  Bottom 2: TP20.T@1 TP20.T@2 TP20.T@3 168.2,34.5
N$81
  Top 0.18: Q7.1 168.95,85 169,85 169.05,85.05 R73.1
N$82  (via drill 0.51)
  Top 0.18: 213,81 v213,77 | 213,81 Q8.3 | R74.1 212.95,81.05 213,81
  Bottom 0.18: 213,34.5 TP21.T@4
  Bottom 0.36: v213,77 213,34.5
  Bottom 2: TP21.T@1 TP21.T@2 TP21.T@3 TP21.T@4
N$83
  Top 0.18: R75.1 214,87 213.95,86.95 Q8.1
N$84
  Top 0.18: 226.7,101.05 226.05,101.05 D7.C | 226.7,101.05 R77.2 229.95,101.05 230,101 C45.2 232.05,101.05 232.25,101.25 R76.2 | 226.7,101.05 226.7,101 226.73,100.97 IC23.3
N$85
  Top 0.18: R78.1 232.05,96.95 232,96.9 | IC23.2 228,97.3 228.4,96.9 232,96.9 | 232,96.9 C46.1
N$86
  Top 0.18: C46.2 232,95 231.9,95.1 227.2,95.1 226.73,94.63 IC23.6 226.73,91.73 226,91 226,87 | R91.2 226,87 | 226,87 230.25,87 233,84.25 R79.1 233,80.75
N$87  (via drill 0.51)
  Top 0.18: v233,77 R79.2
  Bottom 0.18: TP22.T@2 236.9,19.6 236.8,19.5 | TP22.T@4 233,34.5
  Bottom 0.36: 233,34.5 v233,77
  Bottom 2: 236.8,19.5 TP22.T@1 | TP22.T@2 TP22.T@3 TP22.T@4
N$88
  Bottom 0.18: D19.A 257.75,102.7 257.75,102.75 257.8,102.7 D19.A | D19.A D20.K | R89.1 255,103 255.3,102.7 D19.A
N$89  (via drill 0.51)
  Top 0.18: IC24.1 257.06,86 257,86 v257,77
  Bottom 0.36: R81.SENSE2 253.3,53.3 257,57 v257,77
N$90
  Top 0.36: R81.SENSE1 251.54,78.5 251.5,78.5 252.61,79.61 IC24.8
N$91
  Top 0.18: IC24.2 255.16,86.54 254.6,87.1 252.8,87.1 252.7,87.17 IC24.6
N$92
  Top 4: TP23.T@1 TP23.T@4 245.2,34.5 | TP23.T@2 TP23.T@3 245.2,34.5 | 245.2,34.5 245.19,34.5
  Top 7.6: 245.19,34.5 R81.CURRENT2
  Bottom 4: TP23.T@1 TP23.T@4 | TP23.T@3 TP23.T@2
  Bottom 7.6: R81.CURRENT2 245.19,34.5
N$93
  Top 0.18: IC25.3 247.63,88.27 248,87.9 R80.2 249.95,87.95 250,87.9 R82.1 252.45,87.95 IC24.5
N$94
  Top 0.18: R78.2 234,92.5 238.23,88.27 IC25.6 239.4,88.27 239.3,88.2 241.4,88.2 241.55,88.05 | IC25.2 242.6,87 241.55,88.05 | 241.55,88.05 241.55,88 241.5,88 241.5,89.5 242.5,90.5 246.5,90.5 247.5,89.5 262,89.5 262.5,90 262.5,94.25 261.75,95 R86.2
N$95
  Top 0.18: 266,97.3 IC26.2 | 266,97.3 266.4,96.9 269.9,96.9 270,97 C49.1 | R86.1 259.05,95.55 259.75,96.25 265,96.25 266,97.25 266,97.3
N$96
  Top 0.18: C49.2 270,95 269.9,95.1 265,95.1 264.73,94.83 IC26.6 264.73,87 | 264.73,87 264.73,86.98 262,84.25 R83.1 | 264.73,87 R93.2
N$97  (via drill 0.51)
  Top 0.18: v262,77 R83.2
  Bottom 0.18: TP24.T@3 262,34.5
  Bottom 0.36: 262,34.5 v262,77
  Bottom 2: TP24.T@1 TP24.T@2 TP24.T@3 TP24.T@4
N$98
  Top 0.18: R87.1 255.05,91.05 255,91 R84.2 253.05,91.05 253,91.1 | 253,91.1 C51.2 | 253,91.1 249.4,91.1 246.7,93.8 246.7,94 246.5,94.2 245.5,94.2 245.4,94.3 245.4,94.27 IC27.6
N$99
  Top 0.18: IC27.2 253,93 C51.1 254,92.95 | R84.1 255,92.9 254.95,92.95 254,92.95 | 254,92.95 R85.2
N$100
  Top 0.18: 254,96.9 R85.1 254,103.05 246.95,103.05 J5.CONDUCTOR 242.95,102.95 R76.1
  Bottom 0.18: R89.2 254.95,104.95 253,103 247,103 J5.CONDUCTOR
N$101
  Top 0.18: C52.2 259.05,92.95 259,93 R88.2 257.75,92.95 | 257.75,92.95 257.05,92.95 257,93 R87.2 | IC26.3 264.73,97.48 264,96.75 258.5,96.75 257.75,96 257.75,92.95
N$102  (via drill 0.51)
  Top 0.18: 226,81 R90.1 223.05,81.05 223,81 | v223,77 223,81 | 223,81 Q9.3
  Bottom 0.18: 223.2,34.5 223.1,34.6 TP25.T@4 223,34.5
  Bottom 0.36: 223,34.5 v223,77
  Bottom 2: TP25.T@1 TP25.T@2 TP25.T@3 223.2,34.5
N$103
  Top 0.18: Q9.1 223.95,85 224,85 224.05,85.05 R91.1
N$104  (via drill 0.51)
  Top 0.18: v268,77 268,81 | 268,81 Q10.3 | R92.1 267.95,81.05 268,81
  Bottom 0.18: TP26.T@4 268,34.5
  Bottom 0.36: 268,34.5 v268,77
  Bottom 2: TP26.T@1 TP26.T@2 TP26.T@3 TP26.T@4
N$105
  Top 0.18: R93.1 269,87 268.95,86.95 Q10.1
N$106
  Top 0.4: 55,0 55,12
N$107
  Top 0.4: 110,0 110,12
N$108
  Top 0.4: 165,0 165,12
N$109
  Top 0.4: 220,0 220,12
N$110
  Top 0.18: 6.7,101.05 6.05,101.05 D1.C | 6.7,101.05 R8.2 9.95,101.05 10,101 C4.2 R5.2 12,101 | 6.7,101.05 6.7,101 6.73,100.97 IC4.3
N$111
  Top 0.4: 275,0 275,12
N$112
  Bottom 0.5: P1.9 310.16,91.66 308,89.5 305.5,89.5 305,89 305,58 298,51 | 293,51 298,51 | 298,51 F1.1A
N$113
  Top 0.18: D8.A 303.77,94.77 304,95 R94.2 307,95 307.25,94.75 307.32,94.75 P1.4
N$114
  Top 0.18: R9.1 12.05,96.95 12,96.9 | IC4.2 8,97.3 8.4,96.9 12,96.9 | 12,96.9 C5.1
N$115
  Top 0.18: C5.2 12,95 11.9,95.1 7.2,95.1 6.73,94.63 IC4.6 6.73,91.73 6,91 6,87 | R12.2 6,87 | 6,87 10.25,87 13,84.25 R13.1
N$116
  Bottom 0.36: 296,100.5 300.5,100.5 303,103 307.5,103 307.5,103.06 P1.1
  Bottom 0.5: 291,100.28 291,100.5 291.08,100.42 Q11.2 | 296,100.5 295.97,100.5 HS1.2
  Bottom 1: HS1.2 295.97,100 296,100 295.72,100.28 291,100.28 HS1.1
N$117  (via drill 0.51)
  Top 0.18: v13,77 R13.2
  Bottom 0.18: TP2.T@2 16.9,19.6 16.8,19.5 | TP2.T@4 13,34.5
  Bottom 0.36: 13,34.5 v13,77
  Bottom 2: TP2.T@1 16.8,19.5 | TP2.T@2 TP2.T@3 TP2.T@4
N$118
  Top 0.18: R96.CW 302.77,92.23 302.5,92.5 D8.C 300.75,93 | Q11.1 288.54,93.71 289.25,93 300.75,93 | D9.C 301.5,97 300.75,96.25 300.75,93
  Bottom 0.18: R96.W 300.2,86.9 302.74,89.44 R96.CW
N$119
  Top 0.18: D9.A 303.75,97 303.95,97.2 303.95,97.5 | R95.2 303.95,97.5 | 303.95,97.5 304,97.5 304.07,97.57 P1.3
N$120  (via drill 0.51)
  Top 0.18: P1.2 307.25,100.31 307.25,100.25 306.47,101.03 D10.3 | R97.1 293.55,86.95 v293.5,87
  Bottom 0.18: P1.2 307.25,100.31 307.25,100.25 294,87 v293.5,87
N$121
  Bottom 0.18: D11.A D12.K | D11.A 38,102.75 | R3.1 35,103 35.3,102.7 D11.A
N$145  (via drill 0.51)
  Top 0.18: 277.6,109.5 277.5,109.5 277.46,109.54 IC11.3 | 277.6,109.5 C19.2 | 277.6,109.5 277.6,109.16 v279.25,107.5
  Bottom 0.18: F1.2A 277.84,50.9 277.8,50.9 277.9,50.8 | v279.25,107.5 279.25,98.75 287,91 287,77 289.8,74.2 289.8,65.9 291,64.7 292,64.7
  Bottom 0.5: D3.2 292,64.7 292,59.6 283.2,50.8 277.9,50.8
N$146
  Top 0.18: C20.2 277,102.5 | C20.2 R38.1 | C20.2 275.05,102.7 275,102.75 R37.2 275,103.5 274,104.5 IC11.1

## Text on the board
Top: CATS - Bipolar Rev:A1 | Cold Atoms Transfer System | J. Thywissen Labs | University of Toronto - Physics | G1+L | G1+U | D1 | G1-U | G1-L | G2+L | G2+U | D2 | G2-U | G2-L | G3+L | G3+U | D3 | G3-U | G3-L | G4+L | G4+U | D4 | G4-U | G4-L | G5+L | G5+U | D5 | G5-U | G5-L | Com
tDocu: CATS - Bipolar | Cold Atoms Transfer System | A1 | 0.18mm(0.0071") | 7.5mm(0.295") | 0.18mm(0.0071") | n/a | 1mm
